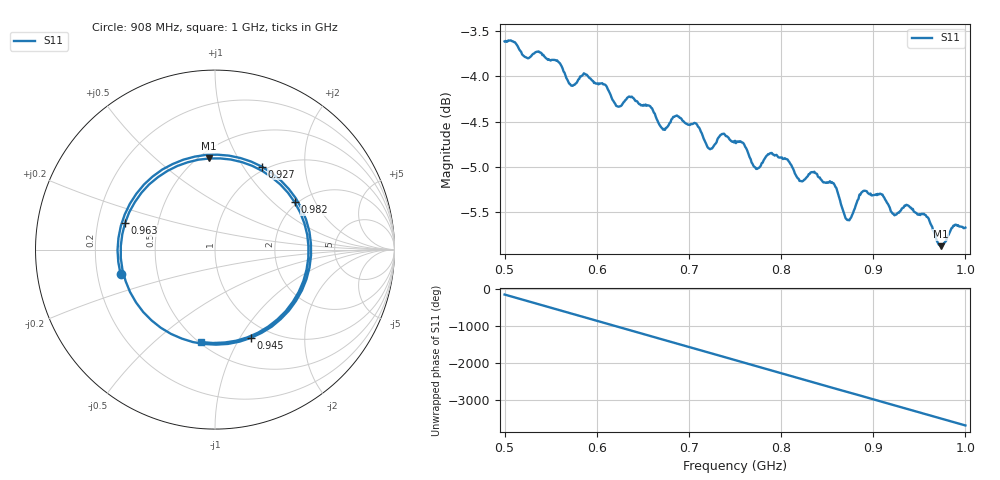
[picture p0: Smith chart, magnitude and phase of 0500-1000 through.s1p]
! NanoVNA-App by SYSJOINT et al v1.1.209 (+OD18)
! Date: 2025-09-17 10:09:25
! Start: 500MHz Stop: 1GHz Points: 501
! S-Parameter data: F S11
# Hz S RI R 50
!  Frequency  S11_Real  S11_Imag
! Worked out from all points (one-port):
!   501 points, 500 MHz to 1 GHz, reference 50 ohm
!   lowest |S11| = -5.9 dB at 973 MHz (marker M1), VSWR 3.07, Z = 28 + j38.4 ohm
!   |S11| at or under -10 dB: nowhere
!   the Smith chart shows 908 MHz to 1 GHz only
!   S11 on the Smith chart (normalised r, x): 908 MHz: 0.30, -0.12; 927 MHz: 0.94, +1.22; 945 MHz: 0.81, -1.12; 963 MHz: 0.32, +0.13; 982 MHz: 1.93, +1.39; 1 GHz: 0.51, -0.72
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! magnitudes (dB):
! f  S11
! 500 MHz  -3.6
! 563 MHz  -3.9
! 572 MHz  -4.1
! 587 MHz  -4.0
! 608 MHz  -4.1
! 625 MHz  -4.3
! 636 MHz  -4.2
! 657 MHz  -4.3
! 672 MHz  -4.6
! 688 MHz  -4.4
! 709 MHz  -4.5
! 722 MHz  -4.8
! 736 MHz  -4.6
! 750 MHz  -4.7
! 773 MHz  -5.0
! 788 MHz  -4.8
! 813 MHz  -5.0
! 856 MHz  -5.2
! 875 MHz  -5.6
! 889 MHz  -5.3
! 908 MHz  -5.3
! 927 MHz  -5.5
! 938 MHz  -5.4
! 945 MHz  -5.5
! 963 MHz  -5.6
! 973 MHz  -5.9
! 982 MHz  -5.7
! 1 GHz  -5.7
